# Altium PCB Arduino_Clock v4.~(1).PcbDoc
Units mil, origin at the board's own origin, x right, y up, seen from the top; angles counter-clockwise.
Board outline 6000 x 4000 mil, 2 copper layers (Top Layer, Bottom Layer); 29 components, 36 nets, 120 pads, 14 vias.

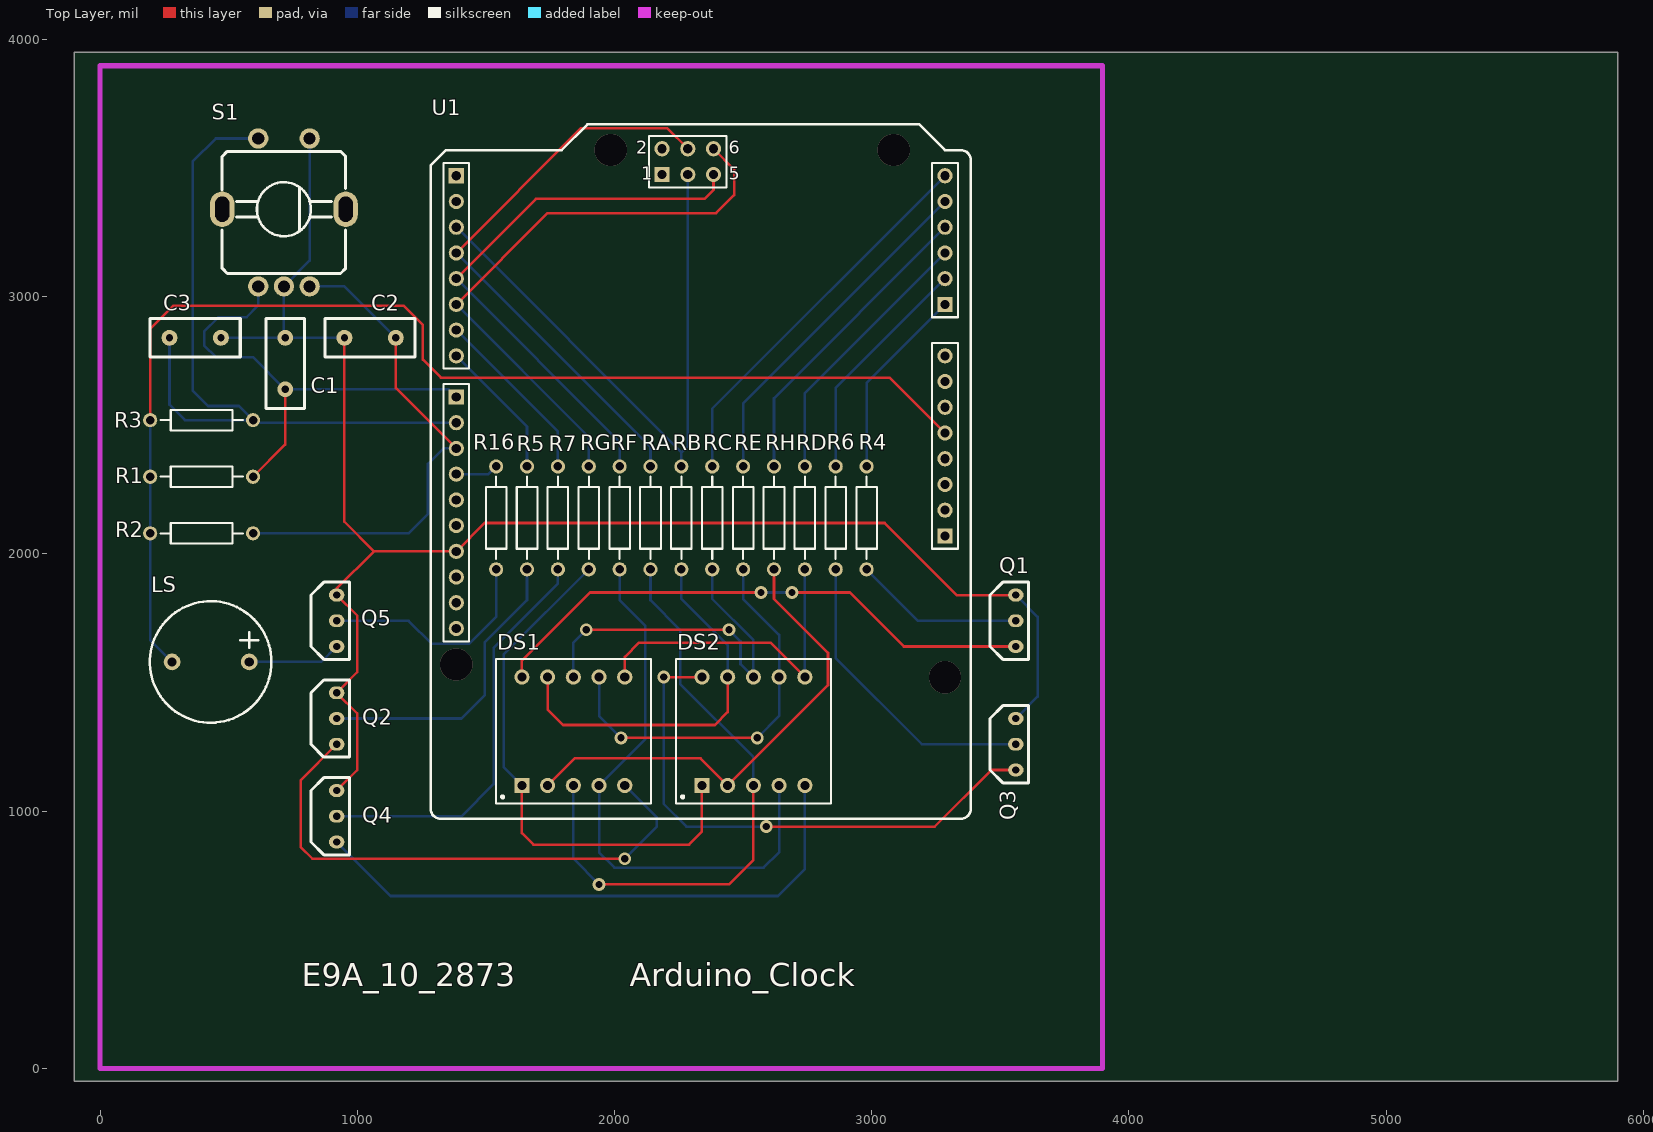
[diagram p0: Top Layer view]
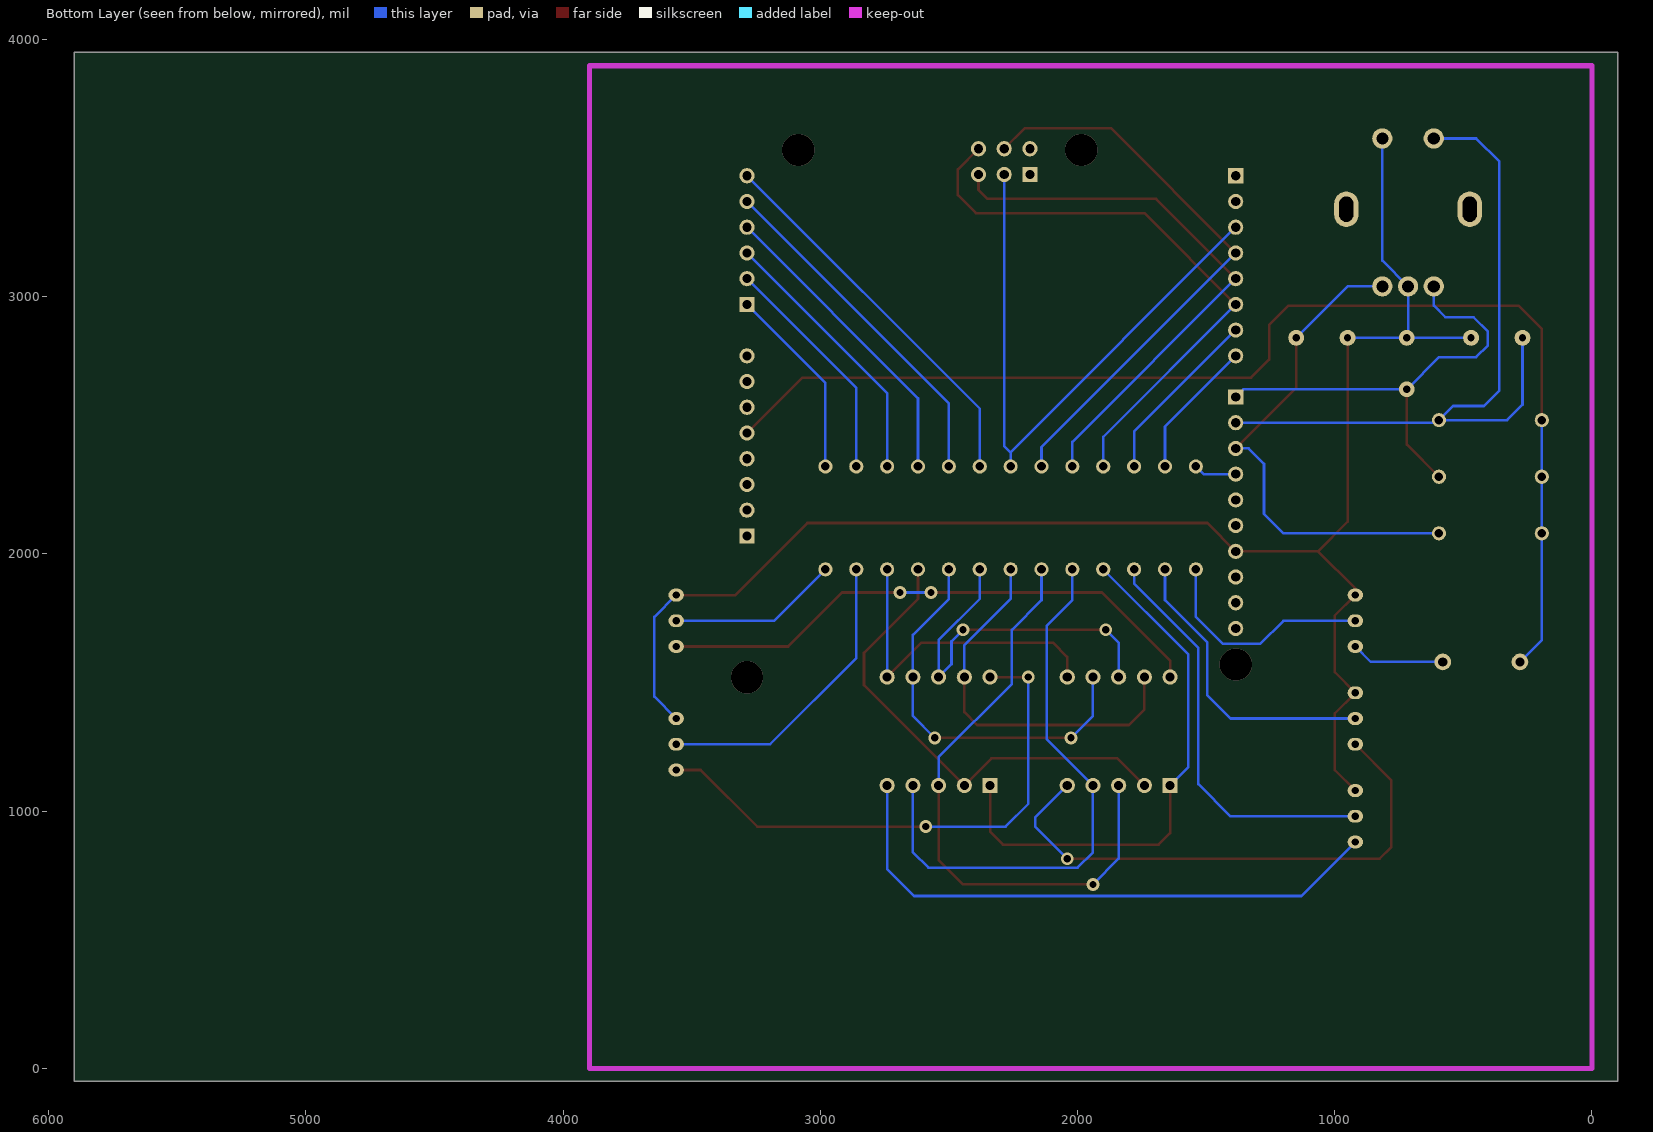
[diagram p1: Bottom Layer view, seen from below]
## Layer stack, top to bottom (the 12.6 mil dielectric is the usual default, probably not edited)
Top Layer: signal copper 1.4
Dielectric: dielectric 12.6, FR-4, Dk 4.8
Bottom Layer: signal copper 1.4

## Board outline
-100,-50 5900,-50 5900,3950 -100,3950

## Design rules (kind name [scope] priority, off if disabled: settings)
Clearance [All] p1 off: gap=10
DiffPairsRouting [All] p1 off: maxlimit=10 minlimit=10 mostfreqgap=10 maxuncoupledlength=500
FanoutControl Fanout_BGA [IsBGA] p1 off: bgadir=Out bgaviamode=Centered fanoutstyle=Auto fanoutdirection=Alternating viagrid=1 // Fanout_BGA (Default Rule)
FanoutControl Fanout_LCC [IsLCC] p2 off: bgadir=Out bgaviamode=Centered fanoutstyle=Auto fanoutdirection=Alternating viagrid=1 // Fanout_LCC (Default Rule)
FanoutControl Fanout_SOIC [IsSOIC] p3 off: bgadir=Out bgaviamode=Centered fanoutstyle=Auto fanoutdirection=Alternating viagrid=1 // Fanout_SOIC (Default Rule)
FanoutControl Fanout_Small [(CompPinCount < 5)] p4 off: bgadir=Out bgaviamode=Centered fanoutstyle=Auto fanoutdirection=OutThenIn viagrid=1 // Fanout_Small (Default Rule)
FanoutControl Fanout_Default [All] p5 off: bgadir=Out bgaviamode=Centered fanoutstyle=Auto fanoutdirection=Alternating viagrid=1 // Fanout_Default (Default Rule)
HoleSize [All] p1 off: absolutevalues=TRUE maxlimit=100 minlimit=1 maxpercent=80.000 minpercent=20.000
HoleToHoleClearance [All] p1 off: gap=10 allowstackedmicrovias=TRUE
LayerPairs [All] p1 off: enforce=TRUE
MinimumSolderMaskSliver [All] p1 off: minsoldermaskwidth=10
NetAntennae [All] p1 off: netantennaetolerance=0
PolygonConnect [All] p1: connectstyle=Relief reliefconductorwidth=10 reliefentries=4 polygonreliefangle="90 Angle"
RoomDefinition "Arduino_Clock v2" [InComponentClass('Arduino_Clock v2')] p1: confinementstyle=ConfineIn formatcopy=TRUE lockcomponents=FALSE outline 5825,-125 14900,-125 14900,2725 5825,2725
RoutingCorners [All] p1 off: cornerstyle=45-Degree minsetback=100 maxsetback=100
RoutingLayers [All] p1 off: top layer_v5=TRUE bottom layer_v5=TRUE
RoutingPriority [All] p1 off: routingpriority=0
RoutingTopology [All] p1 off: topology=Shortest
RoutingVias [All] p1 off: holewidth=28 width=50 viastyle="Through Hole" minholewidth=28 minwidth=50 maxholewidth=28 maxwidth=50
ShortCircuit [All] p1 off: allowed=FALSE
SilkToSilkClearance [All] p1 off: silktosilkclearance=10
SilkscreenOverComponentPads [All] p1 off: minsilkscreentomaskgap=10
SolderMaskExpansion [All] p1: expansion=4
TestPointUsage [All] p1 off: valid=0 allowmultiple=FALSE
Testpoint [All] p1 off: side=15 testpointundercomponent=TRUE minsize=40 maxsize=100 preferedsize=60 minholesize=0 maxholesize=40 preferedholesize=32 testpointgrid=1 style=1023 order=0-112345678
UnRoutedNet [All] p1 off:
Width [All] p1 off: maxlimit=50 minlimit=10 preferedwidth=10
5 further rules are at their usual default settings.

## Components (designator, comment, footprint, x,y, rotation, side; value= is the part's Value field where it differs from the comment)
C1 "Cap" RAD0.2 720,2840 r270 top
C2 "Cap" RAD0.2 950,2840 r0 top
C3 "Cap" RAD0.2 470,2840 r180 top
DS1 "2-DigitDPY" 2-DigitDPY 1640,1100 r0 top
DS2 "2-DigitDPY" 2-DigitDPY 2340,1100 r0 top
LS "Buzzer" Buzzer 580,1580 r180 top
Q1 "NPN" NPN 3560,1640 r90 top
Q2 "NPN" NPN 920,1260 r90 top
Q3 "NPN" NPN 3560,1160 r90 top
Q4 "NPN" NPN 920,880 r90 top
Q5 "NPN" NPN 920,1640 r90 top
R1 "Res2" AXIAL-0.4 395,2300 r0 top
R2 "Res2" AXIAL-0.4 395,2080 r0 top
R3 "Res2" AXIAL-0.4 395,2520 r180 top
R4 "Res2" AXIAL-0.4 2980,2140 r90 top
R5 "Res2" AXIAL-0.4 1660,2140 r270 top
R6 "Res2" AXIAL-0.4 2860,2140 r90 top
R7 "Res2" AXIAL-0.4 1780,2140 r90 top
R16 "Res2" AXIAL-0.4 1540,2140 r270 top
RA "Res2" AXIAL-0.4 2140,2140 r270 top
RB "Res2" AXIAL-0.4 2260,2140 r270 top
RC "Res2" AXIAL-0.4 2380,2140 r270 top
RD "Res2" AXIAL-0.4 2740,2140 r270 top
RE "Res2" AXIAL-0.4 2500,2140 r270 top
RF "Res2" AXIAL-0.4 2020,2140 r270 top
RG "Res2" AXIAL-0.4 1900,2140 r270 top
RH "Res2" AXIAL-0.4 2620,2140 r270 top
S1 "SW-EC11" EC11 715,3340 r0 top
U1 "Arduino" Arduino-UNO 2335,2610 r90 top

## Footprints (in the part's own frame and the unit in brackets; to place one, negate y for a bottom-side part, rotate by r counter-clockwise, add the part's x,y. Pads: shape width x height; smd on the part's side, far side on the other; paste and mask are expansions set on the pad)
2-DigitDPY [mm] "LED, 7-Segment Display, 9.2 mm, Dual Digit; 10 Leads; Row Space 10.7 mm; Pitch 2.54 mm"
  rect 1.5x1.5 hole 0.9: 1(0,0)
  round 1.5 hole 0.9: 2(2.54,0) 3(5.08,0) 4(7.62,0) 5(10.16,0) 6(10.16,10.7) 7(7.62,10.7) 8(5.08,10.7) 9(2.54,10.7) 10(0,10.7)
  silkscreen extent -2.57,-1.8 12.73,12.5
Arduino-UNO [mm] "Arduino板"
  rect 1.5x1.5 hole 0.9: 1(21.844,24.13) 1(21.971,3.81) 9(0,24.13) 19(-13.716,-24.13) 27(9.144,-24.13)
  round 1.5 hole 0.9: 2(19.304,24.13) 2(24.511,3.81) 3(16.764,24.13) 3(21.971,1.27) 4(14.224,24.13) 4(24.511,1.27) 5(11.684,24.13) 5(21.971,-1.27) 6(9.144,24.13) 6(24.511,-1.27) 7(6.604,24.13) 8(4.064,24.13) 10(-2.54,24.13) 11(-5.08,24.13) 12(-7.62,24.13) 13(-10.16,24.13) 14(-12.7,24.13) 15(-15.24,24.13) 16(-17.78,24.13) 17(-20.32,24.13) 18(-22.86,24.13) 20(-11.176,-24.13) 21(-8.636,-24.13) 22(-6.096,-24.13) 23(-3.556,-24.13) 24(-1.016,-24.13) 25(1.524,-24.13) 26(4.064,-24.13) 28(11.684,-24.13) 29(14.224,-24.13) 30(16.764,-24.13) 31(19.304,-24.13) 32(21.844,-24.13)
  silkscreen extent -41.66,-26.67 26.92,26.67
AXIAL-0.4 [mm] "Resistor; 2 Leads"
  round 1.4 hole 0.85: 1(-5.08,0) 2(5.08,0)
  silkscreen extent -4.06,-1.02 4.06,1.02
Buzzer [mil] "蜂鸣器"
  round 65 hole 36: 1(0,0) 2(300,0)
  silkscreen extent -86,-236 386,236
EC11 [mm] "旋转编码器"
  round 2 hole 1.2: 1(-2.54,-7.62) 2(0,-7.62) 3(2.54,-7.62) 4(2.54,6.985) 5(-2.54,6.985)
  oval 2.4x3.5 hole 1.4 slot 2.5 at 90 deg: 6(-6.096,0) 7(6.096,0)
  silkscreen extent -6.1,-6.35 6.1,5.71
NPN [mil]
  oval 50x60 hole 28: 1(0,0) 2(100,0) 3(200,0)
  silkscreen extent -50,-50 250,100
RAD0.2 [mil]
  round 62 hole 28: 1(0,0) 2(200,0)
  silkscreen extent -75,-75 275,75

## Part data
C1 C2 C3: "Capacitor"
DS1 DS2: "9.2 mm Green 7-Segment Display: 2-Digit, RH DP"
LS: "Magnetic Transducer Buzzer"
Q1 Q2 Q3 Q4 Q5: "NPN Bipolar Transistor"
R1 R2 R3 R4 R5 R6 R7 R16 RA RB RC RD RE RF RG RH: "Resistor"
S1: "旋转编码开关"
U1: library part Arduino-UNO

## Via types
v1: diameter 50, hole 28, Top Layer to Bottom Layer, 10 vias
v2: diameter 125.98, hole 125.98, Top Layer to Bottom Layer, 4 vias

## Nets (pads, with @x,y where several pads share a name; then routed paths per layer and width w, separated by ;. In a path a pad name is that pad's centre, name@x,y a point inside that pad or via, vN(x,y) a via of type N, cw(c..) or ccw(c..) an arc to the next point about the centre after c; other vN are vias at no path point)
5V: LS.2 R1.1 R2.1 R3.2 U1.23 | length 4751.6
  Top Layer w10: R3.2 195,2875 285,2965 1180,2965 1255,2890 1255,2755 1325,2685 3070,2685 U1.23
  Bottom Layer w10: R2.1 R1.1 R3.2 ; R2.1@195,2090 195,1665 LS.2
A: DS1.3 DS2.3 RA.2 | length 2361.5
  Top Layer w10: v1(1940,715) 2445,715 2540,810 DS2.3
  Bottom Layer w10: DS1.3 1840,815 v1(1940,715) ; RA.2 2140,1820 2255,1705 2255,1495 2540,1210 DS2.3
B: DS1.9 DS2.9 RB.2 | length 1501.4
  Top Layer w10: DS1.9 1740,1395 1800,1335 2390,1335 2440,1385 DS2.9
  Bottom Layer w10: RB.2 2260,1825 2440,1645 DS2.9
C: DS1.8 DS2.8 RC.2 | length 1467.6
  Top Layer w10: v1(1890,1705) v1(2445,1705)
  Bottom Layer w10: DS1.8 1840,1655 v1(1890,1705) ; RC.2 2380,1825 2540,1665 DS2.8 2490,1571.26 2490,1660 v1(2445,1705)
D: DS1.6 DS2.6 RD.2 | length 1275.7
  Top Layer w10: DS1.6 2040,1600 2095,1655 2606.26,1655 DS2.6
  Bottom Layer w10: DS2.6 RD.2
D2: RB.1 U1.3 | length 2382.8
  Bottom Layer w10: U1.3@1385,3270 2260,2395 ; RB.1 2260,2395 ; U1.3@2285,3475 2285,2420 2260,2395
D3: RA.1 U1.4 | length 2276.8
  Top Layer w10: U1.4@1385,3170 1870,3655 2205,3655 U1.4@2285,3575
  Bottom Layer w10: U1.4@1385,3170 2140,2415 RA.1
D4: RF.1 U1.5 | length 2195.9
  Top Layer w10: U1.5@1385,3070 1695,3380 2350,3380 2385,3415 U1.5@2385,3475
  Bottom Layer w10: U1.5@1385,3070 2020,2435 RF.1
D5: RG.1 U1.6 | length 2312.5
  Top Layer w10: U1.6@1385,2970 1740,3325 2395,3325 2465,3395 2465,3495 U1.6@2385,3575
  Bottom Layer w10: U1.6@1385,2970 1900,2455 RG.1
D6: R7.2 U1.7 | length 693.6
  Bottom Layer w10: U1.7 1780,2475 R7.2
D7: R5.1 U1.8 | length 543.9
  Bottom Layer w10: U1.8 1660,2495 R5.1
D8: C1.2 R1.2 S1.1 U1.9 | length 1843.1
  Top Layer w10: R1.2 720,2425 C1.2
  Bottom Layer w10: S1.1 615,2965 570,2920 460,2920 405,2865 405,2810 450,2765 595,2765 C1.2 ; C1.2@715,2635 C1.2 ; U1.9 1355,2640 C1.2
D9: C3.2 R3.1 S1.5 U1.10 | length 2868.9
  Bottom Layer w10: C3.2 270,2580 330,2520 R3.1 ; S1.5 450,3615 360,3525 360,2635 420,2575 540,2575 R3.1 ; U1.10 605,2510 R3.1
D10: C2.2 R2.2 S1.3 U1.11 | length 1986.1
  Top Layer w10: C2.2 1150,2645 U1.11
  Bottom Layer w10: R2.2 1200,2080 1275,2155 1275,2350 1335,2410 U1.11 ; S1.3 950,3040 C2.2
D11: R16.1 U1.12 | length 167.4
  Bottom Layer w10: U1.12 1510,2310 R16.1
D14: R4.2 U1.27 | length 756.3
  Bottom Layer w10: R4.2 2980,2665 U1.27
D15: R6.2 U1.28 | length 906
  Bottom Layer w10: R6.2 2860,2645 U1.28
D16: RD.1 U1.29 | length 1055.7
  Bottom Layer w10: RD.1 2740,2625 U1.29
D17: RH.1 U1.30 | length 1205.5
  Bottom Layer w10: RH.1 2620,2605 U1.30
D18: RE.1 U1.31 | length 1355.2
  Bottom Layer w10: RE.1 2500,2585 U1.31
D19: RC.1 U1.32 | length 1504.9
  Bottom Layer w10: RC.1 2380,2565 U1.32
E: DS1.7 DS2.7 RE.2 | length 1549.7
  Top Layer w10: v1(2025,1285) v1(2555,1285)
  Bottom Layer w10: DS1.7 1940,1370 v1(2025,1285) ; RE.2 2500,1825 2640,1685 DS2.7 2640,1370 v1(2555,1285)
F: DS1.4 DS2.4 RF.2 | length 2225.7
  Bottom Layer w10: RF.2 2020,1820 2120,1720 2120,1280 DS1.4 1940,840 2000,780 2580,780 2640,840 DS2.4
G: DS1.1 DS2.1 RG.2 | length 2110
  Top Layer w10: DS1.1 1640,915 1685,870 2290,870 2340,920 DS2.1
  Bottom Layer w10: DS1.1 1570,1170 1570,1610 RG.2
GND: C1.1 C2.1 C3.1 Q1.3 Q2.3 Q3.3 Q4.3 Q5.3 S1.2 S1.4 U1.15 | length 6505.7
  Top Layer w10: Q4.3 1000,1160 1000,1380 Q2.3 1000,1540 1000,1760 Q5.3 920,1865 1065,2010 ; C2.1 950,2125 1065,2010 ; Q1.3 3330,1840 3050,2120 1495,2120 U1.15 1065,2010
  Bottom Layer w10: C3.1 C1.1 ; S1.4 815,3140 S1.2 715,2845 C1.1 ; C2.1 C1.1 ; Q3.3 3645,1445 3645,1755 Q1.3
NetDS1_2: DS1.2 DS2.2 RH.2 | length 1875.5
  Top Layer w10: DS1.2 1845,1205 2335,1205 DS2.2 2830,1490 2830,1615 2620,1825 RH.2
NetDS1_5: DS1.5 Q2.1 | length 2125.2
  Top Layer w10: Q2.1 780,1120 780,860 825,815 v1(2040,815)
  Bottom Layer w10: v1(2040,815) 2165,940 2165,975 DS1.5
NetDS1_10: DS1.10 Q1.1 | length 2180.5
  Top Layer w10: DS1.10 1640,1585 1905,1850 v1(2570,1850) ; v1(2690,1850) 2915,1850 3125,1640 Q1.1
  Bottom Layer w10: v1(2570,1850) v1(2690,1850)
NetDS2_5: DS2.5 Q4.1 | length 2275.5
  Bottom Layer w10: Q4.1 1130,670 2635,670 2740,775 DS2.5
NetDS2_10: DS2.10 Q3.1 | length 2137.9
  Top Layer w10: v1(2191.26,1521.26) DS2.10 ; v1(2590,940) 3245,940 3465,1160 Q3.1
  Bottom Layer w10: v1(2191.26,1521.26) 2191.26,1028.74 2280,940 v1(2590,940)
NetLS_1: LS.1 Q5.1 | length 364.9
  Bottom Layer w10: LS.1 860,1580 Q5.1
NetQ1_2: Q1.2 R4.1 | length 662.8
  Bottom Layer w10: R4.1 3180,1740 Q1.2
NetQ2_2: Q2.2 R5.2 | length 1170.6
  Bottom Layer w10: Q2.2 1405,1360 1495,1450 1495,1655 1660,1820 R5.2
NetQ3_2: Q3.2 R6.1 | length 1183.8
  Bottom Layer w10: R6.1 2860,1595 3195,1260 Q3.2
NetQ4_2: Q4.2 R7.1 | length 1600.3
  Bottom Layer w10: Q4.2 1405,980 1530,1105 1530,1635 1780,1885 R7.1
NetQ5_2: Q5.2 R16.2 | length 885.8
  Bottom Layer w10: Q5.2 1200,1740 1290,1650 1435,1650 1540,1755 R16.2
pads on no net: S1.6 S1.7 U1.1 U1.2 U1.13 U1.14 U1.16 U1.17 U1.18 U1.19 U1.20 U1.21 U1.22 U1.24 U1.25 U1.26
copper on no net:
  other v2: 3285,1520 1385,1570 1985,3570 3085,3570

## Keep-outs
Keep-Out Layer:
  lines w20: 0,0 0,3897.64 3897.64,3897.64 3897.64,0 0,0

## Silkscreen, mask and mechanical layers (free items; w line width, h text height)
Top Overlay:
  text "E9A_10_2873" at 785,320 h90
  text "Arduino_Clock" at 2060,320 h90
